VERSION 5.7 ;
  NOWIREEXTENSIONATPIN ON ;
  DIVIDERCHAR "/" ;
  BUSBITCHARS "[]" ;
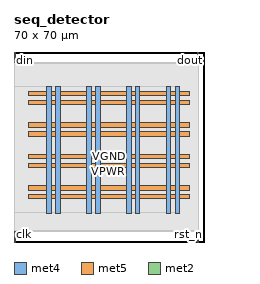
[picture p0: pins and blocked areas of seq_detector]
MACRO seq_detector
  CLASS BLOCK ;
  FOREIGN seq_detector ;
  ORIGIN 0.000 0.000 ;
  SIZE 70.000 BY 70.000 ;
  PIN VGND
    DIRECTION INOUT ;
    USE GROUND ;
    PORT
      LAYER met4 ;
        RECT 15.380 10.640 16.980 57.360 ;
    END
    PORT
      LAYER met4 ;
        RECT 30.100 10.640 31.700 57.360 ;
    END
    PORT
      LAYER met4 ;
        RECT 44.820 10.640 46.420 57.360 ;
    END
    PORT
      LAYER met4 ;
        RECT 59.540 10.640 61.140 57.360 ;
    END
    PORT
      LAYER met5 ;
        RECT 5.280 19.155 64.640 20.755 ;
    END
    PORT
      LAYER met5 ;
        RECT 5.280 30.710 64.640 32.310 ;
    END
    PORT
      LAYER met5 ;
        RECT 5.280 42.265 64.640 43.865 ;
    END
    PORT
      LAYER met5 ;
        RECT 5.280 53.820 64.640 55.420 ;
    END
  END VGND
  PIN VPWR
    DIRECTION INOUT ;
    USE POWER ;
    PORT
      LAYER met4 ;
        RECT 12.080 10.640 13.680 57.360 ;
    END
    PORT
      LAYER met4 ;
        RECT 26.800 10.640 28.400 57.360 ;
    END
    PORT
      LAYER met4 ;
        RECT 41.520 10.640 43.120 57.360 ;
    END
    PORT
      LAYER met4 ;
        RECT 56.240 10.640 57.840 57.360 ;
    END
    PORT
      LAYER met5 ;
        RECT 5.280 15.855 64.640 17.455 ;
    END
    PORT
      LAYER met5 ;
        RECT 5.280 27.410 64.640 29.010 ;
    END
    PORT
      LAYER met5 ;
        RECT 5.280 38.965 64.640 40.565 ;
    END
    PORT
      LAYER met5 ;
        RECT 5.280 50.520 64.640 52.120 ;
    END
  END VPWR
  PIN clk
    DIRECTION INPUT ;
    USE SIGNAL ;
    ANTENNAGATEAREA 0.852000 ;
    PORT
      LAYER met2 ;
        RECT 0.090 0.000 0.370 4.000 ;
    END
  END clk
  PIN din
    DIRECTION INPUT ;
    USE SIGNAL ;
    ANTENNAGATEAREA 0.196500 ;
    PORT
      LAYER met2 ;
        RECT 0.090 66.000 0.370 70.000 ;
    END
  END din
  PIN dout
    DIRECTION OUTPUT TRISTATE ;
    USE SIGNAL ;
    ANTENNADIFFAREA 0.795200 ;
    PORT
      LAYER met2 ;
        RECT 67.710 66.000 67.990 70.000 ;
    END
  END dout
  PIN rst_n
    DIRECTION INPUT ;
    USE SIGNAL ;
    ANTENNAGATEAREA 0.196500 ;
    PORT
      LAYER met2 ;
        RECT 67.710 0.000 67.990 4.000 ;
    END
  END rst_n
  OBS
      LAYER li1 ;
        RECT 5.520 10.795 64.400 57.205 ;
      LAYER met1 ;
        RECT 0.070 10.640 68.010 57.360 ;
      LAYER met2 ;
        RECT 0.650 65.720 67.430 66.000 ;
        RECT 0.090 4.280 67.980 65.720 ;
        RECT 0.650 4.000 67.430 4.280 ;
      LAYER met3 ;
        RECT 0.065 10.715 61.130 57.285 ;
  END
END seq_detector
END LIBRARY

